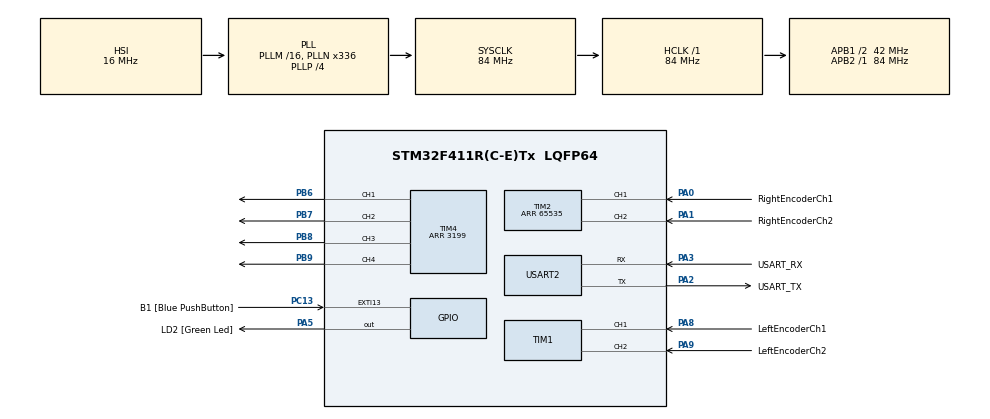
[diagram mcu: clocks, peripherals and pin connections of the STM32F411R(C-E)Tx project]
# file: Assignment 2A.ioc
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Mcu.Family=STM32F4
Mcu.Name=STM32F411R(C-E)Tx
Mcu.Package=LQFP64
NVIC.PriorityGroup=NVIC_PRIORITYGROUP_0
NVIC.TIM4_IRQn=true\:0\:0\:false\:false\:true\:true\:true\:true
PA0-WKUP.GPIO_Label=RightEncoderCh1
PA0-WKUP.Signal=S_TIM2_CH1_ETR
PA1.GPIO_Label=RightEncoderCh2
PA1.Signal=S_TIM2_CH2
PA13.GPIO_Label=TMS
PA13.Mode=Serial_Wire
PA13.Signal=SYS_JTMS-SWDIO
PA14.GPIO_Label=TCK
PA14.Mode=Serial_Wire
PA14.Signal=SYS_JTCK-SWCLK
PA2.GPIO_Label=USART_TX
PA2.Mode=Asynchronous
PA2.Signal=USART2_TX
PA3.GPIO_Label=USART_RX
PA3.Mode=Asynchronous
PA3.Signal=USART2_RX
PA5.GPIO_Label=LD2 [Green Led]
PA5.Signal=GPIO_Output
PA8.GPIO_Label=LeftEncoderCh1
PA8.Signal=S_TIM1_CH1
PA9.GPIO_Label=LeftEncoderCh2
PA9.Signal=S_TIM1_CH2
PB3.GPIO_Label=SWO
PB3.Signal=SYS_JTDO-SWO
PB6.Signal=S_TIM4_CH1
PB7.Signal=S_TIM4_CH2
PB8.Signal=S_TIM4_CH3
PB9.Signal=S_TIM4_CH4
PC13-ANTI_TAMP.GPIO_Label=B1 [Blue PushButton]
PC13-ANTI_TAMP.GPIO_ModeDefaultEXTI=GPIO_MODE_IT_FALLING
PC13-ANTI_TAMP.Signal=GPXTI13
PC14-OSC32_IN.Mode=LSE-External-Oscillator
PC14-OSC32_IN.Signal=RCC_OSC32_IN
PC15-OSC32_OUT.Mode=LSE-External-Oscillator
PC15-OSC32_OUT.Signal=RCC_OSC32_OUT
PH0\ -\ OSC_IN.Mode=HSE-External-Clock-Source
PH0\ -\ OSC_IN.Signal=RCC_OSC_IN
PH1\ -\ OSC_OUT.Mode=HSE-External-Clock-Source
PH1\ -\ OSC_OUT.Signal=RCC_OSC_OUT
ProjectManager.HeapSize=0x200
ProjectManager.StackSize=0x400
ProjectManager.TargetToolchain=STM32CubeIDE
RCC.48MHZClocksFreq_Value=84000000
RCC.AHBFreq_Value=84000000
RCC.APB1CLKDivider=RCC_HCLK_DIV2
RCC.APB1Freq_Value=42000000
RCC.APB1TimFreq_Value=84000000
RCC.APB2Freq_Value=84000000
RCC.APB2TimFreq_Value=84000000
RCC.CortexFreq_Value=84000000
RCC.FLatency-AdvancedSettings=FLASH_LATENCY_2
RCC.HCLKFreq_Value=84000000
RCC.HSE_VALUE=8000000
RCC.HSI_VALUE=16000000
RCC.PLLN=336
RCC.PLLP=RCC_PLLP_DIV4
RCC.SYSCLKFreq_VALUE=84000000
RCC.SYSCLKSource=RCC_SYSCLKSOURCE_PLLCLK
RCC.VCOOutputFreq_Value=336000000
SH.S_TIM1_CH1.0=TIM1_CH1,Encoder_Interface
SH.S_TIM1_CH2.0=TIM1_CH2,Encoder_Interface
SH.S_TIM2_CH1_ETR.0=TIM2_CH1,Encoder_Interface
SH.S_TIM2_CH2.0=TIM2_CH2,Encoder_Interface
SH.S_TIM4_CH1.0=TIM4_CH1,PWM Generation1 CH1
SH.S_TIM4_CH2.0=TIM4_CH2,PWM Generation2 CH2
SH.S_TIM4_CH3.0=TIM4_CH3,PWM Generation3 CH3
SH.S_TIM4_CH4.0=TIM4_CH4,PWM Generation4 CH4
TIM1.EncoderMode=TIM_ENCODERMODE_TI12
TIM2.EncoderMode=TIM_ENCODERMODE_TI12
TIM2.Period=65535
TIM4.Channel-PWM\ Generation1\ CH1=TIM_CHANNEL_1
TIM4.Channel-PWM\ Generation2\ CH2=TIM_CHANNEL_2
TIM4.Channel-PWM\ Generation3\ CH3=TIM_CHANNEL_3
TIM4.Channel-PWM\ Generation4\ CH4=TIM_CHANNEL_4
TIM4.Period=3199
USART2.VirtualMode=VM_ASYNC
board=NUCLEO-F411RE

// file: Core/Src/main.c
/* USER CODE BEGIN Header */
/**
  ******************************************************************************
  * @file           : main.c
  * @brief          : Main program body
  ******************************************************************************
  * @attention
  *
  * Copyright (c) 2026 STMicroelectronics.
  * All rights reserved.
  *
  * This software is licensed under terms that can be found in the LICENSE file
  * in the root directory of this software component.
  * If no LICENSE file comes with this software, it is provided AS-IS.
  *
  ******************************************************************************
  */
/* USER CODE END Header */
#include "main.h"

/* USER CODE BEGIN Includes */
#include "encoders.h"
#include "motors.h"
#include "controller.h"
#include "pid.h"
/* USER CODE END Includes */

TIM_HandleTypeDef htim1;
TIM_HandleTypeDef htim2;
TIM_HandleTypeDef htim4;

UART_HandleTypeDef huart2;

/* USER CODE BEGIN PV */
	int16_t left_counts = 0;
	int16_t right_counts = 0;
	int timerMain = 0;

/* USER CODE END PV */

void SystemClock_Config(void);
static void MX_GPIO_Init(void);
static void MX_USART2_UART_Init(void);
static void MX_TIM1_Init(void);
static void MX_TIM2_Init(void);
static void MX_TIM4_Init(void);

int main(void)
{

  /* MCU Configuration--------------------------------------------------------*/

  /* Reset of all peripherals, Initializes the Flash interface and the Systick. */
  HAL_Init();

  /* Configure the system clock */
  SystemClock_Config();

  /* Initialize all configured peripherals */
  MX_GPIO_Init();
  MX_USART2_UART_Init();
  MX_TIM1_Init();
  MX_TIM2_Init();
  MX_TIM4_Init();
  /* USER CODE BEGIN 2 */
  	HAL_TIM_Encoder_Start(&htim1, TIM_CHANNEL_ALL);
    HAL_TIM_Encoder_Start(&htim2, TIM_CHANNEL_ALL);
    HAL_TIM_PWM_Start(&htim4, TIM_CHANNEL_1);
    HAL_TIM_PWM_Start(&htim4, TIM_CHANNEL_2);
    HAL_TIM_PWM_Start(&htim4, TIM_CHANNEL_3);
    HAL_TIM_PWM_Start(&htim4, TIM_CHANNEL_4);

//    setMotorRPWM(0.9);
//    setMotorLPWM(-0.8);

//    while ( timerMain <= 10000){
//    	timerMain = getPidCount();
//    };

    //turn(-2);
    timerMain=1;
    turn(1);
    timerMain = 6;
    move(1);
    timerMain++;

  /* USER CODE END 2 */

  /* Infinite loop */
  while (1)
  {
	  left_counts = getLeftEncoderCounts();
	  right_counts = getRightEncoderCounts();
  }
}

void SystemClock_Config(void)
{
  RCC_OscInitTypeDef RCC_OscInitStruct = {0};
  RCC_ClkInitTypeDef RCC_ClkInitStruct = {0};

  /** Configure the main internal regulator output voltage
  */
  __HAL_RCC_PWR_CLK_ENABLE();
  __HAL_PWR_VOLTAGESCALING_CONFIG(PWR_REGULATOR_VOLTAGE_SCALE1);

  /** Initializes the RCC Oscillators according to the specified parameters
  * in the RCC_OscInitTypeDef structure.
  */
  RCC_OscInitStruct.OscillatorType = RCC_OSCILLATORTYPE_HSI;
  RCC_OscInitStruct.HSIState = RCC_HSI_ON;
  RCC_OscInitStruct.HSICalibrationValue = RCC_HSICALIBRATION_DEFAULT;
  RCC_OscInitStruct.PLL.PLLState = RCC_PLL_ON;
  RCC_OscInitStruct.PLL.PLLSource = RCC_PLLSOURCE_HSI;
  RCC_OscInitStruct.PLL.PLLM = 16;
  RCC_OscInitStruct.PLL.PLLN = 336;
  RCC_OscInitStruct.PLL.PLLP = RCC_PLLP_DIV4;
  RCC_OscInitStruct.PLL.PLLQ = 4;
  if (HAL_RCC_OscConfig(&RCC_OscInitStruct) != HAL_OK)
  {
    Error_Handler();
  }

  /** Initializes the CPU, AHB and APB buses clocks
  */
  RCC_ClkInitStruct.ClockType = RCC_CLOCKTYPE_HCLK|RCC_CLOCKTYPE_SYSCLK
                              |RCC_CLOCKTYPE_PCLK1|RCC_CLOCKTYPE_PCLK2;
  RCC_ClkInitStruct.SYSCLKSource = RCC_SYSCLKSOURCE_PLLCLK;
  RCC_ClkInitStruct.AHBCLKDivider = RCC_SYSCLK_DIV1;
  RCC_ClkInitStruct.APB1CLKDivider = RCC_HCLK_DIV2;
  RCC_ClkInitStruct.APB2CLKDivider = RCC_HCLK_DIV1;

  if (HAL_RCC_ClockConfig(&RCC_ClkInitStruct, FLASH_LATENCY_2) != HAL_OK)
  {
    Error_Handler();
  }
}

static void MX_TIM1_Init(void)
{

  TIM_Encoder_InitTypeDef sConfig = {0};
  TIM_MasterConfigTypeDef sMasterConfig = {0};

  htim1.Instance = TIM1;
  htim1.Init.Prescaler = 0;
  htim1.Init.CounterMode = TIM_COUNTERMODE_UP;
  htim1.Init.Period = 65535;
  htim1.Init.ClockDivision = TIM_CLOCKDIVISION_DIV1;
  htim1.Init.RepetitionCounter = 0;
  htim1.Init.AutoReloadPreload = TIM_AUTORELOAD_PRELOAD_DISABLE;
  sConfig.EncoderMode = TIM_ENCODERMODE_TI12;
  sConfig.IC1Polarity = TIM_ICPOLARITY_RISING;
  sConfig.IC1Selection = TIM_ICSELECTION_DIRECTTI;
  sConfig.IC1Prescaler = TIM_ICPSC_DIV1;
  sConfig.IC1Filter = 0;
  sConfig.IC2Polarity = TIM_ICPOLARITY_RISING;
  sConfig.IC2Selection = TIM_ICSELECTION_DIRECTTI;
  sConfig.IC2Prescaler = TIM_ICPSC_DIV1;
  sConfig.IC2Filter = 0;
  if (HAL_TIM_Encoder_Init(&htim1, &sConfig) != HAL_OK)
  {
    Error_Handler();
  }
  sMasterConfig.MasterOutputTrigger = TIM_TRGO_RESET;
  sMasterConfig.MasterSlaveMode = TIM_MASTERSLAVEMODE_DISABLE;
  if (HAL_TIMEx_MasterConfigSynchronization(&htim1, &sMasterConfig) != HAL_OK)
  {
    Error_Handler();
  }

}

static void MX_TIM2_Init(void)
{

  TIM_Encoder_InitTypeDef sConfig = {0};
  TIM_MasterConfigTypeDef sMasterConfig = {0};

  htim2.Instance = TIM2;
  htim2.Init.Prescaler = 0;
  htim2.Init.CounterMode = TIM_COUNTERMODE_UP;
  htim2.Init.Period = 65535;
  htim2.Init.ClockDivision = TIM_CLOCKDIVISION_DIV1;
  htim2.Init.AutoReloadPreload = TIM_AUTORELOAD_PRELOAD_DISABLE;
  sConfig.EncoderMode = TIM_ENCODERMODE_TI12;
  sConfig.IC1Polarity = TIM_ICPOLARITY_RISING;
  sConfig.IC1Selection = TIM_ICSELECTION_DIRECTTI;
  sConfig.IC1Prescaler = TIM_ICPSC_DIV1;
  sConfig.IC1Filter = 0;
  sConfig.IC2Polarity = TIM_ICPOLARITY_RISING;
  sConfig.IC2Selection = TIM_ICSELECTION_DIRECTTI;
  sConfig.IC2Prescaler = TIM_ICPSC_DIV1;
  sConfig.IC2Filter = 0;
  if (HAL_TIM_Encoder_Init(&htim2, &sConfig) != HAL_OK)
  {
    Error_Handler();
  }
  sMasterConfig.MasterOutputTrigger = TIM_TRGO_RESET;
  sMasterConfig.MasterSlaveMode = TIM_MASTERSLAVEMODE_DISABLE;
  if (HAL_TIMEx_MasterConfigSynchronization(&htim2, &sMasterConfig) != HAL_OK)
  {
    Error_Handler();
  }

}

static void MX_TIM4_Init(void)
{

  TIM_MasterConfigTypeDef sMasterConfig = {0};
  TIM_OC_InitTypeDef sConfigOC = {0};

  htim4.Instance = TIM4;
  htim4.Init.Prescaler = 0;
  htim4.Init.CounterMode = TIM_COUNTERMODE_UP;
  htim4.Init.Period = 3199;
  htim4.Init.ClockDivision = TIM_CLOCKDIVISION_DIV1;
  htim4.Init.AutoReloadPreload = TIM_AUTORELOAD_PRELOAD_DISABLE;
  if (HAL_TIM_PWM_Init(&htim4) != HAL_OK)
  {
    Error_Handler();
  }
  sMasterConfig.MasterOutputTrigger = TIM_TRGO_RESET;
  sMasterConfig.MasterSlaveMode = TIM_MASTERSLAVEMODE_DISABLE;
  if (HAL_TIMEx_MasterConfigSynchronization(&htim4, &sMasterConfig) != HAL_OK)
  {
    Error_Handler();
  }
  sConfigOC.OCMode = TIM_OCMODE_PWM1;
  sConfigOC.Pulse = 0;
  sConfigOC.OCPolarity = TIM_OCPOLARITY_HIGH;
  sConfigOC.OCFastMode = TIM_OCFAST_DISABLE;
  if (HAL_TIM_PWM_ConfigChannel(&htim4, &sConfigOC, TIM_CHANNEL_1) != HAL_OK)
  {
    Error_Handler();
  }
  if (HAL_TIM_PWM_ConfigChannel(&htim4, &sConfigOC, TIM_CHANNEL_2) != HAL_OK)
  {
    Error_Handler();
  }
  if (HAL_TIM_PWM_ConfigChannel(&htim4, &sConfigOC, TIM_CHANNEL_3) != HAL_OK)
  {
    Error_Handler();
  }
  if (HAL_TIM_PWM_ConfigChannel(&htim4, &sConfigOC, TIM_CHANNEL_4) != HAL_OK)
  {
    Error_Handler();
  }
  HAL_TIM_MspPostInit(&htim4);

}

static void MX_USART2_UART_Init(void)
{

  huart2.Instance = USART2;
  huart2.Init.BaudRate = 115200;
  huart2.Init.WordLength = UART_WORDLENGTH_8B;
  huart2.Init.StopBits = UART_STOPBITS_1;
  huart2.Init.Parity = UART_PARITY_NONE;
  huart2.Init.Mode = UART_MODE_TX_RX;
  huart2.Init.HwFlowCtl = UART_HWCONTROL_NONE;
  huart2.Init.OverSampling = UART_OVERSAMPLING_16;
  if (HAL_UART_Init(&huart2) != HAL_OK)
  {
    Error_Handler();
  }

}

static void MX_GPIO_Init(void)
{
  GPIO_InitTypeDef GPIO_InitStruct = {0};

  /* GPIO Ports Clock Enable */
  __HAL_RCC_GPIOC_CLK_ENABLE();
  __HAL_RCC_GPIOH_CLK_ENABLE();
  __HAL_RCC_GPIOA_CLK_ENABLE();
  __HAL_RCC_GPIOB_CLK_ENABLE();

  /*Configure GPIO pin Output Level */
  HAL_GPIO_WritePin(Button_GPIO_Port, Button_Pin, GPIO_PIN_RESET);

  /*Configure GPIO pin : LED_Pin */
  GPIO_InitStruct.Pin = LED_Pin;
  GPIO_InitStruct.Mode = GPIO_MODE_IT_RISING_FALLING;
  GPIO_InitStruct.Pull = GPIO_NOPULL;
  HAL_GPIO_Init(LED_GPIO_Port, &GPIO_InitStruct);

  /*Configure GPIO pin : Button_Pin */
  GPIO_InitStruct.Pin = Button_Pin;
  GPIO_InitStruct.Mode = GPIO_MODE_OUTPUT_PP;
  GPIO_InitStruct.Pull = GPIO_NOPULL;
  GPIO_InitStruct.Speed = GPIO_SPEED_FREQ_LOW;
  HAL_GPIO_Init(Button_GPIO_Port, &GPIO_InitStruct);

  /* EXTI interrupt init*/
  HAL_NVIC_SetPriority(EXTI15_10_IRQn, 0, 0);
  HAL_NVIC_EnableIRQ(EXTI15_10_IRQn);

}

void Error_Handler(void)
{
  __disable_irq();
  while (1)
  {
  }
}
